VERSION 5.7 ;
  NOWIREEXTENSIONATPIN ON ;
  DIVIDERCHAR "/" ;
  BUSBITCHARS "[]" ;
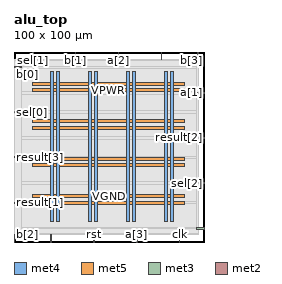
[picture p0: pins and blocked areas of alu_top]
MACRO alu_top
  CLASS BLOCK ;
  FOREIGN alu_top ;
  ORIGIN 0.000 0.000 ;
  SIZE 100.000 BY 100.000 ;
  PIN VGND
    DIRECTION INOUT ;
    USE GROUND ;
    PORT
      LAYER met4 ;
        RECT 22.565 10.640 24.165 90.000 ;
    END
    PORT
      LAYER met4 ;
        RECT 42.460 10.640 44.060 90.000 ;
    END
    PORT
      LAYER met4 ;
        RECT 62.355 10.640 63.955 90.000 ;
    END
    PORT
      LAYER met4 ;
        RECT 82.250 10.640 83.850 90.000 ;
    END
    PORT
      LAYER met5 ;
        RECT 9.880 23.240 89.940 24.840 ;
    END
    PORT
      LAYER met5 ;
        RECT 9.880 42.960 89.940 44.560 ;
    END
    PORT
      LAYER met5 ;
        RECT 9.880 62.680 89.940 64.280 ;
    END
    PORT
      LAYER met5 ;
        RECT 9.880 82.400 89.940 84.000 ;
    END
  END VGND
  PIN VPWR
    DIRECTION INOUT ;
    USE POWER ;
    PORT
      LAYER met4 ;
        RECT 19.265 10.640 20.865 90.000 ;
    END
    PORT
      LAYER met4 ;
        RECT 39.160 10.640 40.760 90.000 ;
    END
    PORT
      LAYER met4 ;
        RECT 59.055 10.640 60.655 90.000 ;
    END
    PORT
      LAYER met4 ;
        RECT 78.950 10.640 80.550 90.000 ;
    END
    PORT
      LAYER met5 ;
        RECT 9.880 19.940 89.940 21.540 ;
    END
    PORT
      LAYER met5 ;
        RECT 9.880 39.660 89.940 41.260 ;
    END
    PORT
      LAYER met5 ;
        RECT 9.880 59.380 89.940 60.980 ;
    END
    PORT
      LAYER met5 ;
        RECT 9.880 79.100 89.940 80.700 ;
    END
  END VPWR
  PIN a[0]
    DIRECTION INPUT ;
    USE SIGNAL ;
    ANTENNAGATEAREA 0.213000 ;
    PORT
      LAYER met3 ;
        RECT 96.000 6.840 100.000 7.440 ;
    END
  END a[0]
  PIN a[1]
    DIRECTION INPUT ;
    USE SIGNAL ;
    ANTENNAGATEAREA 0.213000 ;
    PORT
      LAYER met3 ;
        RECT 96.000 78.240 100.000 78.840 ;
    END
  END a[1]
  PIN a[2]
    DIRECTION INPUT ;
    USE SIGNAL ;
    ANTENNAGATEAREA 0.159000 ;
    PORT
      LAYER met2 ;
        RECT 54.830 96.000 55.110 100.000 ;
    END
  END a[2]
  PIN a[3]
    DIRECTION INPUT ;
    USE SIGNAL ;
    ANTENNAGATEAREA 0.213000 ;
    PORT
      LAYER met2 ;
        RECT 64.490 0.000 64.770 4.000 ;
    END
  END a[3]
  PIN b[0]
    DIRECTION INPUT ;
    USE SIGNAL ;
    ANTENNAGATEAREA 0.159000 ;
    PORT
      LAYER met3 ;
        RECT 0.000 91.840 4.000 92.440 ;
    END
  END b[0]
  PIN b[1]
    DIRECTION INPUT ;
    USE SIGNAL ;
    ANTENNAGATEAREA 0.213000 ;
    PORT
      LAYER met2 ;
        RECT 32.290 96.000 32.570 100.000 ;
    END
  END b[1]
  PIN b[2]
    DIRECTION INPUT ;
    USE SIGNAL ;
    ANTENNAGATEAREA 0.159000 ;
    PORT
      LAYER met2 ;
        RECT 0.090 0.000 0.370 4.000 ;
    END
  END b[2]
  PIN b[3]
    DIRECTION INPUT ;
    USE SIGNAL ;
    ANTENNAGATEAREA 0.213000 ;
    PORT
      LAYER met2 ;
        RECT 96.690 96.000 96.970 100.000 ;
    END
  END b[3]
  PIN clk
    DIRECTION INPUT ;
    USE SIGNAL ;
    ANTENNAGATEAREA 0.852000 ;
    PORT
      LAYER met2 ;
        RECT 87.030 0.000 87.310 4.000 ;
    END
  END clk
  PIN result[0]
    DIRECTION OUTPUT TRISTATE ;
    USE SIGNAL ;
    ANTENNADIFFAREA 0.795200 ;
    PORT
      LAYER met2 ;
        RECT 19.410 0.000 19.690 4.000 ;
    END
  END result[0]
  PIN result[1]
    DIRECTION OUTPUT TRISTATE ;
    USE SIGNAL ;
    ANTENNADIFFAREA 0.795200 ;
    PORT
      LAYER met3 ;
        RECT 0.000 20.440 4.000 21.040 ;
    END
  END result[1]
  PIN result[2]
    DIRECTION OUTPUT TRISTATE ;
    USE SIGNAL ;
    ANTENNADIFFAREA 0.795200 ;
    PORT
      LAYER met3 ;
        RECT 96.000 54.440 100.000 55.040 ;
    END
  END result[2]
  PIN result[3]
    DIRECTION OUTPUT TRISTATE ;
    USE SIGNAL ;
    ANTENNADIFFAREA 0.795200 ;
    PORT
      LAYER met3 ;
        RECT 0.000 44.240 4.000 44.840 ;
    END
  END result[3]
  PIN result[4]
    DIRECTION OUTPUT TRISTATE ;
    USE SIGNAL ;
    ANTENNADIFFAREA 0.795200 ;
    PORT
      LAYER met2 ;
        RECT 77.370 96.000 77.650 100.000 ;
    END
  END result[4]
  PIN rst
    DIRECTION INPUT ;
    USE SIGNAL ;
    ANTENNAGATEAREA 0.196500 ;
    PORT
      LAYER met2 ;
        RECT 41.950 0.000 42.230 4.000 ;
    END
  END rst
  PIN sel[0]
    DIRECTION INPUT ;
    USE SIGNAL ;
    ANTENNAGATEAREA 0.126000 ;
    PORT
      LAYER met3 ;
        RECT 0.000 68.040 4.000 68.640 ;
    END
  END sel[0]
  PIN sel[1]
    DIRECTION INPUT ;
    USE SIGNAL ;
    ANTENNAGATEAREA 0.196500 ;
    PORT
      LAYER met2 ;
        RECT 9.750 96.000 10.030 100.000 ;
    END
  END sel[1]
  PIN sel[2]
    DIRECTION INPUT ;
    USE SIGNAL ;
    ANTENNAGATEAREA 0.196500 ;
    PORT
      LAYER met3 ;
        RECT 96.000 30.640 100.000 31.240 ;
    END
  END sel[2]
  OBS
      LAYER li1 ;
        RECT 10.120 10.795 89.700 89.845 ;
      LAYER met1 ;
        RECT 0.070 10.640 96.990 90.000 ;
      LAYER met2 ;
        RECT 0.100 95.720 9.470 96.000 ;
        RECT 10.310 95.720 32.010 96.000 ;
        RECT 32.850 95.720 54.550 96.000 ;
        RECT 55.390 95.720 77.090 96.000 ;
        RECT 77.930 95.720 96.410 96.000 ;
        RECT 0.100 4.280 96.960 95.720 ;
        RECT 0.650 4.000 19.130 4.280 ;
        RECT 19.970 4.000 41.670 4.280 ;
        RECT 42.510 4.000 64.210 4.280 ;
        RECT 65.050 4.000 86.750 4.280 ;
        RECT 87.590 4.000 96.960 4.280 ;
      LAYER met3 ;
        RECT 4.400 91.440 96.000 92.290 ;
        RECT 4.000 79.240 96.000 91.440 ;
        RECT 4.000 77.840 95.600 79.240 ;
        RECT 4.000 69.040 96.000 77.840 ;
        RECT 4.400 67.640 96.000 69.040 ;
        RECT 4.000 55.440 96.000 67.640 ;
        RECT 4.000 54.040 95.600 55.440 ;
        RECT 4.000 45.240 96.000 54.040 ;
        RECT 4.400 43.840 96.000 45.240 ;
        RECT 4.000 31.640 96.000 43.840 ;
        RECT 4.000 30.240 95.600 31.640 ;
        RECT 4.000 21.440 96.000 30.240 ;
        RECT 4.400 20.040 96.000 21.440 ;
        RECT 4.000 7.840 96.000 20.040 ;
        RECT 4.000 6.975 95.600 7.840 ;
  END
END alu_top
END LIBRARY

